One B-rep face of a CAD part: STEP entity #10473.
In plain terms, the planar face has unit normal (0, 1, 0).
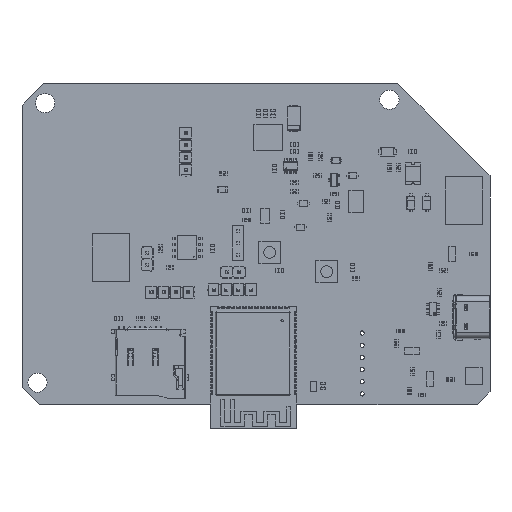
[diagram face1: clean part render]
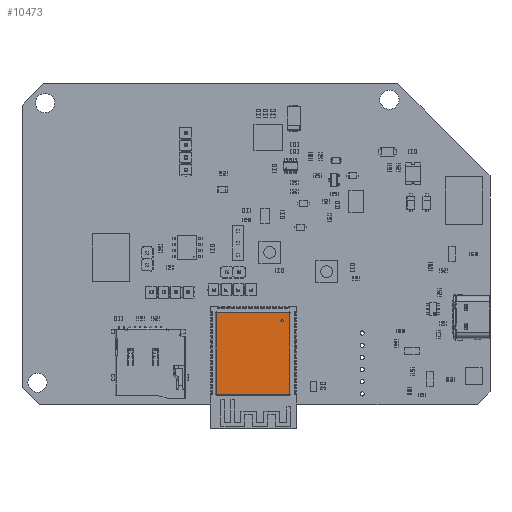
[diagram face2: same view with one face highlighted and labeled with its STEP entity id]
Its self-contained STEP definition (entity closure, numbers rounded to 3 decimals):
#9794 = VERTEX_POINT('',#9795);
#9795 = CARTESIAN_POINT('',(-6.,3.25,10.));
#9801 = EDGE_CURVE('',#9802,#9794,#9804,.T.);
#9802 = VERTEX_POINT('',#9803);
#9803 = CARTESIAN_POINT('',(-6.,3.25,9.5));
#9804 = CIRCLE('',#9805,0.25);
#9805 = AXIS2_PLACEMENT_3D('',#9806,#9807,#9808);
#9806 = CARTESIAN_POINT('',(-6.,3.25,9.75));
#9807 = DIRECTION('',(0.,1.,0.));
#9808 = DIRECTION('',(0.,-0.,1.));
#9844 = VERTEX_POINT('',#9845);
#9845 = CARTESIAN_POINT('',(7.749,3.25,11.429));
#9852 = EDGE_CURVE('',#9844,#9853,#9855,.T.);
#9853 = VERTEX_POINT('',#9854);
#9854 = CARTESIAN_POINT('',(7.729,3.25,11.429));
#9855 = LINE('',#9856,#9857);
#9856 = CARTESIAN_POINT('',(8.,3.25,11.429));
#9857 = VECTOR('',#9858,1.);
#9858 = DIRECTION('',(-1.,0.,0.));
#9965 = VERTEX_POINT('',#9966);
#9966 = CARTESIAN_POINT('',(7.729,3.25,-5.629));
#9972 = EDGE_CURVE('',#9965,#9973,#9975,.T.);
#9973 = VERTEX_POINT('',#9974);
#9974 = CARTESIAN_POINT('',(7.749,3.25,-5.629));
#9975 = LINE('',#9976,#9977);
#9976 = CARTESIAN_POINT('',(8.,3.25,-5.629));
#9977 = VECTOR('',#9978,1.);
#9978 = DIRECTION('',(1.,-0.,-0.));
#10014 = VERTEX_POINT('',#10015);
#10015 = CARTESIAN_POINT('',(7.729,3.25,-5.649));
#10022 = EDGE_CURVE('',#10014,#9965,#10023,.T.);
#10023 = LINE('',#10024,#10025);
#10024 = CARTESIAN_POINT('',(7.729,3.25,-5.629));
#10025 = VECTOR('',#10026,1.);
#10026 = DIRECTION('',(-0.,-0.,1.));
#10126 = VERTEX_POINT('',#10127);
#10127 = CARTESIAN_POINT('',(-7.529,3.25,-5.629));
#10133 = EDGE_CURVE('',#10126,#10134,#10136,.T.);
#10134 = VERTEX_POINT('',#10135);
#10135 = CARTESIAN_POINT('',(-7.529,3.25,-5.649));
#10136 = LINE('',#10137,#10138);
#10137 = CARTESIAN_POINT('',(-7.529,3.25,-5.629));
#10138 = VECTOR('',#10139,1.);
#10139 = DIRECTION('',(0.,0.,-1.));
#10175 = VERTEX_POINT('',#10176);
#10176 = CARTESIAN_POINT('',(-7.549,3.25,-5.629));
#10183 = EDGE_CURVE('',#10175,#10126,#10184,.T.);
#10184 = LINE('',#10185,#10186);
#10185 = CARTESIAN_POINT('',(-7.529,3.25,-5.629));
#10186 = VECTOR('',#10187,1.);
#10187 = DIRECTION('',(1.,-0.,-0.));
#10287 = VERTEX_POINT('',#10288);
#10288 = CARTESIAN_POINT('',(-7.529,3.25,11.429));
#10294 = EDGE_CURVE('',#10287,#10295,#10297,.T.);
#10295 = VERTEX_POINT('',#10296);
#10296 = CARTESIAN_POINT('',(-7.549,3.25,11.429));
#10297 = LINE('',#10298,#10299);
#10298 = CARTESIAN_POINT('',(-7.529,3.25,11.429));
#10299 = VECTOR('',#10300,1.);
#10300 = DIRECTION('',(-1.,0.,0.));
#10336 = VERTEX_POINT('',#10337);
#10337 = CARTESIAN_POINT('',(-7.529,3.25,11.449));
#10344 = EDGE_CURVE('',#10336,#10287,#10345,.T.);
#10345 = LINE('',#10346,#10347);
#10346 = CARTESIAN_POINT('',(-7.529,3.25,11.7));
#10347 = VECTOR('',#10348,1.);
#10348 = DIRECTION('',(0.,0.,-1.));
#10446 = EDGE_CURVE('',#9853,#10447,#10449,.T.);
#10447 = VERTEX_POINT('',#10448);
#10448 = CARTESIAN_POINT('',(7.729,3.25,11.449));
#10449 = LINE('',#10450,#10451);
#10450 = CARTESIAN_POINT('',(7.729,3.25,11.7));
#10451 = VECTOR('',#10452,1.);
#10452 = DIRECTION('',(-0.,-0.,1.));
#10473 = ADVANCED_FACE('',(#10474,#10484),#10518,.F.);
#10474 = FACE_BOUND('',#10475,.T.);
#10475 = EDGE_LOOP('',(#10476,#10483));
#10476 = ORIENTED_EDGE('',*,*,#10477,.F.);
#10477 = EDGE_CURVE('',#9794,#9802,#10478,.T.);
#10478 = CIRCLE('',#10479,0.25);
#10479 = AXIS2_PLACEMENT_3D('',#10480,#10481,#10482);
#10480 = CARTESIAN_POINT('',(-6.,3.25,9.75));
#10481 = DIRECTION('',(0.,1.,0.));
#10482 = DIRECTION('',(0.,-0.,1.));
#10483 = ORIENTED_EDGE('',*,*,#9801,.F.);
#10484 = FACE_BOUND('',#10485,.T.);
#10485 = EDGE_LOOP('',(#10486,#10492,#10493,#10494,#10500,#10501,#10502,
    #10508,#10509,#10510,#10516,#10517));
#10486 = ORIENTED_EDGE('',*,*,#10487,.T.);
#10487 = EDGE_CURVE('',#10014,#10134,#10488,.T.);
#10488 = LINE('',#10489,#10490);
#10489 = CARTESIAN_POINT('',(0.,3.25,-5.649));
#10490 = VECTOR('',#10491,1.);
#10491 = DIRECTION('',(-1.,-0.,-0.));
#10492 = ORIENTED_EDGE('',*,*,#10133,.F.);
#10493 = ORIENTED_EDGE('',*,*,#10183,.F.);
#10494 = ORIENTED_EDGE('',*,*,#10495,.T.);
#10495 = EDGE_CURVE('',#10175,#10295,#10496,.T.);
#10496 = LINE('',#10497,#10498);
#10497 = CARTESIAN_POINT('',(-7.549,3.25,0.));
#10498 = VECTOR('',#10499,1.);
#10499 = DIRECTION('',(-0.,-0.,1.));
#10500 = ORIENTED_EDGE('',*,*,#10294,.F.);
#10501 = ORIENTED_EDGE('',*,*,#10344,.F.);
#10502 = ORIENTED_EDGE('',*,*,#10503,.T.);
#10503 = EDGE_CURVE('',#10336,#10447,#10504,.T.);
#10504 = LINE('',#10505,#10506);
#10505 = CARTESIAN_POINT('',(0.,3.25,11.449));
#10506 = VECTOR('',#10507,1.);
#10507 = DIRECTION('',(1.,-0.,-0.));
#10508 = ORIENTED_EDGE('',*,*,#10446,.F.);
#10509 = ORIENTED_EDGE('',*,*,#9852,.F.);
#10510 = ORIENTED_EDGE('',*,*,#10511,.T.);
#10511 = EDGE_CURVE('',#9844,#9973,#10512,.T.);
#10512 = LINE('',#10513,#10514);
#10513 = CARTESIAN_POINT('',(7.749,3.25,0.));
#10514 = VECTOR('',#10515,1.);
#10515 = DIRECTION('',(-0.,-0.,-1.));
#10516 = ORIENTED_EDGE('',*,*,#9972,.F.);
#10517 = ORIENTED_EDGE('',*,*,#10022,.F.);
#10518 = PLANE('',#10519);
#10519 = AXIS2_PLACEMENT_3D('',#10520,#10521,#10522);
#10520 = CARTESIAN_POINT('',(0.,3.25,0.));
#10521 = DIRECTION('',(0.,-1.,0.));
#10522 = DIRECTION('',(0.,-0.,-1.));
